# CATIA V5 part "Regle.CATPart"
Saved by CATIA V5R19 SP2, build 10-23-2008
Part number: Regle
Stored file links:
  D:\SCHOOL\FRANCE\BANC_POUTRE_EN_MOUSSE\Regle.CATPart

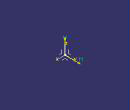
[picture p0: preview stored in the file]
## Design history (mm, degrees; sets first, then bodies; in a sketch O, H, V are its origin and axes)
AxisSystem1: origin (0, 0, 0), X (1, 0, 0), Y (0, 1, 0), Z (0, 0, 1)
Body1 (main body)
  Sketch1 on YZ plane of AxisSystem1, origin (0, 0, 0), H (0, 1, 0), V (0, 0, 1)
